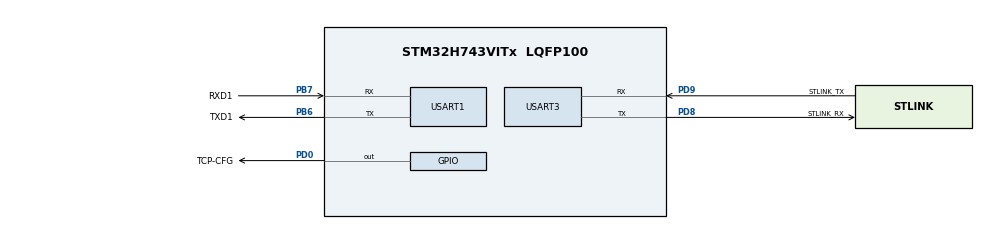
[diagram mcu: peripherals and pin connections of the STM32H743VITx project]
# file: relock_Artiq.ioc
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CORTEX_M7.CPU_DCache=Disabled
CORTEX_M7.CPU_ICache=Disabled
CORTEX_M7.MPU_Control=__NULL
CORTEX_M7.default_mode_Activation=0
Mcu.Family=STM32H7
Mcu.Name=STM32H743VITx
Mcu.Package=LQFP100
NVIC.PriorityGroup=NVIC_PRIORITYGROUP_4
PA13\ (JTMS/SWDIO).Mode=JTAG_4_pins
PA13\ (JTMS/SWDIO).Signal=DEBUG_JTMS-SWDIO
PA14\ (JTCK/SWCLK).Mode=JTAG_4_pins
PA14\ (JTCK/SWCLK).Signal=DEBUG_JTCK-SWCLK
PA15\ (JTDI).Mode=JTAG_4_pins
PA15\ (JTDI).Signal=DEBUG_JTDI
PB3\ (JTDO/TRACESWO).Mode=JTAG_4_pins
PB3\ (JTDO/TRACESWO).Signal=DEBUG_JTDO-SWO
PB6.GPIO_Label=TXD1
PB6.Mode=Asynchronous
PB6.Signal=USART1_TX
PB7.GPIO_Label=RXD1
PB7.Mode=Asynchronous
PB7.Signal=USART1_RX
PD0.GPIO_Label=TCP-CFG
PD0.PinState=GPIO_PIN_SET
PD0.Signal=GPIO_Output
PD8.GPIO_Label=STLINK_RX
PD8.Mode=Asynchronous
PD8.Signal=USART3_TX
PD9.GPIO_Label=STLINK_TX
PD9.Mode=Asynchronous
PD9.Signal=USART3_RX
PH0-OSC_IN\ (PH0).Mode=HSE-External-Oscillator
PH0-OSC_IN\ (PH0).Signal=RCC_OSC_IN
PH1-OSC_OUT\ (PH1).Mode=HSE-External-Oscillator
PH1-OSC_OUT\ (PH1).Signal=RCC_OSC_OUT
ProjectManager.HeapSize=0x200
ProjectManager.StackSize=0x400
ProjectManager.TargetToolchain=STM32CubeIDE
RCC.ADCFreq_Value=75000000
RCC.APB1Freq_Value=75000000
RCC.APB2Freq_Value=75000000
RCC.APB3Freq_Value=75000000
RCC.APB4Freq_Value=75000000
RCC.CortexFreq_Value=75000000
RCC.DIVM1=1
RCC.DIVM2=1
RCC.DIVN1=18
RCC.DIVN2=18
RCC.DIVQ1=3
RCC.HCLKFreq_Value=75000000
RCC.HSE_VALUE=8000000
RCC.PLLSourceVirtual=RCC_PLLSOURCE_HSE
RCC.SYSCLKFreq_VALUE=75000000
RCC.SYSCLKSource=RCC_SYSCLKSOURCE_PLLCLK
RCC.USBFreq_Value=50000000
USART1.VirtualMode-Asynchronous=VM_ASYNC
USART3.VirtualMode-Asynchronous=VM_ASYNC
VP_MEMORYMAP_VS_MEMORYMAP.Mode=CurAppReg
board=NUCLEO-H743ZI2

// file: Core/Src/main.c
/* USER CODE BEGIN Header */
/**
  ******************************************************************************
  * @file           : main.c
  * @brief          : Main program body
  ******************************************************************************
  * @attention
  *
  * Copyright (c) 2024 STMicroelectronics.
  * All rights reserved.
  *
  * This software is licensed under terms that can be found in the LICENSE file
  * in the root directory of this software component.
  * If no LICENSE file comes with this software, it is provided AS-IS.
  *
  ******************************************************************************
  */
/* USER CODE END Header */
#include "main.h"

/* USER CODE BEGIN Includes */
#include "interface.h"
/* USER CODE END Includes */

/* USER CODE BEGIN PD */
#define FLASH_PARAM_START_ADDR  ((uint32_t)0x081E0000)  // bank 2, sektor 7
#define FLASH_WORD_SIZE        (32)  // Flash word = 256-bit = 32 bytes
#define BUFFER_SIZE 100
#define MAX(a,b) (((a)>(b))?(a):(b))
/* USER CODE END PD */

UART_HandleTypeDef huart1;
UART_HandleTypeDef huart3;

/* USER CODE BEGIN PV */
uint8_t rxChar;
  uint8_t rxBuffer[BUFFER_SIZE];
  uint8_t txBuffer[BUFFER_SIZE];
  uint8_t tmpBuffer[BUFFER_SIZE];
  uint16_t index = 0;
  uint8_t helloMsg[] = "\nADDA>";
  HAL_StatusTypeDef status;

void Flash_Write_Params(uint32_t address, parameters *data) {
  HAL_FLASH_Unlock();  // Odblokowanie pamięci flash

  FLASH_EraseInitTypeDef eraseInitStruct;
  uint32_t sectorError;

  // Kasowanie sektora przed zapisem
  eraseInitStruct.TypeErase    = FLASH_TYPEERASE_SECTORS;
  eraseInitStruct.Banks        = FLASH_BANK_2;  // **Bank 2**
  eraseInitStruct.Sector       = FLASH_SECTOR_7;  // **Sektor 7**
  eraseInitStruct.NbSectors    = 1;
  eraseInitStruct.VoltageRange = FLASH_VOLTAGE_RANGE_3;

  if (HAL_FLASHEx_Erase(&eraseInitStruct, &sectorError) != HAL_OK) {
      HAL_FLASH_Lock();
      return;  // Błąd kasowania
  }

  uint64_t *data_ptr = (uint64_t*)data;
  uint64_t flash_word[4];
  for (uint32_t i = 0; i < sizeof(parameters) / 8; i += 4) {
      flash_word[0] = (i < sizeof(parameters) / 8) ? data_ptr[i] : 0xFFFFFFFFFFFFFFFF;
      flash_word[1] = (i + 1 < sizeof(parameters) / 8) ? data_ptr[i + 1] : 0xFFFFFFFFFFFFFFFF;
      flash_word[2] = (i + 2 < sizeof(parameters) / 8) ? data_ptr[i + 2] : 0xFFFFFFFFFFFFFFFF;
      flash_word[3] = (i + 3 < sizeof(parameters) / 8) ? data_ptr[i + 3] : 0xFFFFFFFFFFFFFFFF;

      if (HAL_FLASH_Program(FLASH_TYPEPROGRAM_FLASHWORD, address + i * 8, (uint64_t)flash_word) != HAL_OK) {
          HAL_FLASH_Lock();
          return;  // Błąd zapisu
      }
  }

  HAL_FLASH_Lock();  // Zablokowanie pamięci flash
}

void Flash_Read_Params(uint32_t address, parameters *data) {
  memcpy(data, (void*)address, sizeof(parameters));  // Odczytaj całą strukturę
}

uint32_t Flash_Read_Version(uint32_t address) {
  return *(volatile double*)address;  // Odczytaj pierwsze 4 bajty
}

/* USER CODE END PV */

void SystemClock_Config(void);
static void MX_GPIO_Init(void);
static void MX_USART3_UART_Init(void);
static void MX_USART1_UART_Init(void);
/* USER CODE BEGIN PFP */
void SendSpiMesToDac(uint32_t);
void SetDAC(uint8_t channel, uint16_t value);
void SendToDAC(int r);
int ExtractMessageOld(char* msg, char* out);
void ExtractMessage(char* rxBuffer, char* txBuffer);
void arrayToString(double DAC[4][4], char *result);
void update_array();
/* USER CODE END PFP */

/* USER CODE BEGIN 0 */
extern parameters par;
/* USER CODE END 0 */

int main(void)
{

  /* MCU Configuration--------------------------------------------------------*/

  /* Reset of all peripherals, Initializes the Flash interface and the Systick. */
  HAL_Init();

  /* Configure the system clock */
  SystemClock_Config();

  /* Initialize all configured peripherals */
  MX_GPIO_Init();
  MX_USART3_UART_Init();
  MX_USART1_UART_Init();
  /* USER CODE BEGIN 2 */

  initInterface();

  // read par from flash
  if (par.version != Flash_Read_Version(FLASH_PARAM_START_ADDR)){
    Flash_Write_Params(FLASH_PARAM_START_ADDR, &par);
  }
  else{
    Flash_Read_Params(FLASH_PARAM_START_ADDR, &par);
  }

  /* USER CODE END 2 */

  /* Infinite loop */
  /* USER CODE BEGIN WHILE */
  while (1)
  {
	  status = HAL_UART_Receive(&huart1, &rxChar, 1, HAL_MAX_DELAY);
	  	  	  	  if (status == HAL_OK)
	  	  	  	  {
	  	  	  		  if ((rxChar == '\r' || rxChar == '\n') && index>0){
	  	  	  			  rxBuffer[index++]='\n';
	  	  	  			  rxBuffer[index++]='\0';
	  	  	  			  ExtractMessage((char*) rxBuffer, (char*) txBuffer);
	  //	  	  			  strcpy(tmpBuffer, helloMsg);
	  	  	  			  strcat(tmpBuffer, txBuffer);
	  	  	  			  strcpy(txBuffer, tmpBuffer);

	  	  	  			  HAL_UART_Transmit(&huart1, txBuffer, strlen(txBuffer), HAL_MAX_DELAY);
	  	  	  			  HAL_UART_Transmit(&huart1, helloMsg, strlen(helloMsg), HAL_MAX_DELAY);
	  	  	  			  index=0;
	  	  	  		  }
	  	  	  		  else{
	  	  	  			  rxBuffer[index++] = rxChar;
	  	  	  			  if (index >= BUFFER_SIZE) index = 0;
	  	  	  		  }
	  	  	  	  }
    /* USER CODE END WHILE */

  }
}

void SystemClock_Config(void)
{
  RCC_OscInitTypeDef RCC_OscInitStruct = {0};
  RCC_ClkInitTypeDef RCC_ClkInitStruct = {0};

  /** Supply configuration update enable
  */
  HAL_PWREx_ConfigSupply(PWR_LDO_SUPPLY);

  /** Configure the main internal regulator output voltage
  */
  __HAL_PWR_VOLTAGESCALING_CONFIG(PWR_REGULATOR_VOLTAGE_SCALE3);

  while(!__HAL_PWR_GET_FLAG(PWR_FLAG_VOSRDY)) {}

  /** Initializes the RCC Oscillators according to the specified parameters
  * in the RCC_OscInitTypeDef structure.
  */
  RCC_OscInitStruct.OscillatorType = RCC_OSCILLATORTYPE_HSE;
  RCC_OscInitStruct.HSEState = RCC_HSE_ON;
  RCC_OscInitStruct.PLL.PLLState = RCC_PLL_ON;
  RCC_OscInitStruct.PLL.PLLSource = RCC_PLLSOURCE_HSE;
  RCC_OscInitStruct.PLL.PLLM = 1;
  RCC_OscInitStruct.PLL.PLLN = 18;
  RCC_OscInitStruct.PLL.PLLP = 2;
  RCC_OscInitStruct.PLL.PLLQ = 3;
  RCC_OscInitStruct.PLL.PLLR = 2;
  RCC_OscInitStruct.PLL.PLLRGE = RCC_PLL1VCIRANGE_3;
  RCC_OscInitStruct.PLL.PLLVCOSEL = RCC_PLL1VCOMEDIUM;
  RCC_OscInitStruct.PLL.PLLFRACN = 0;
  if (HAL_RCC_OscConfig(&RCC_OscInitStruct) != HAL_OK)
  {
    Error_Handler();
  }

  /** Initializes the CPU, AHB and APB buses clocks
  */
  RCC_ClkInitStruct.ClockType = RCC_CLOCKTYPE_HCLK|RCC_CLOCKTYPE_SYSCLK
                              |RCC_CLOCKTYPE_PCLK1|RCC_CLOCKTYPE_PCLK2
                              |RCC_CLOCKTYPE_D3PCLK1|RCC_CLOCKTYPE_D1PCLK1;
  RCC_ClkInitStruct.SYSCLKSource = RCC_SYSCLKSOURCE_PLLCLK;
  RCC_ClkInitStruct.SYSCLKDivider = RCC_SYSCLK_DIV1;
  RCC_ClkInitStruct.AHBCLKDivider = RCC_HCLK_DIV1;
  RCC_ClkInitStruct.APB3CLKDivider = RCC_APB3_DIV1;
  RCC_ClkInitStruct.APB1CLKDivider = RCC_APB1_DIV1;
  RCC_ClkInitStruct.APB2CLKDivider = RCC_APB2_DIV1;
  RCC_ClkInitStruct.APB4CLKDivider = RCC_APB4_DIV1;

  if (HAL_RCC_ClockConfig(&RCC_ClkInitStruct, FLASH_LATENCY_1) != HAL_OK)
  {
    Error_Handler();
  }
}

static void MX_USART1_UART_Init(void)
{

  huart1.Instance = USART1;
  huart1.Init.BaudRate = 115200;
  huart1.Init.WordLength = UART_WORDLENGTH_8B;
  huart1.Init.StopBits = UART_STOPBITS_1;
  huart1.Init.Parity = UART_PARITY_NONE;
  huart1.Init.Mode = UART_MODE_TX_RX;
  huart1.Init.HwFlowCtl = UART_HWCONTROL_NONE;
  huart1.Init.OverSampling = UART_OVERSAMPLING_16;
  huart1.Init.OneBitSampling = UART_ONE_BIT_SAMPLE_DISABLE;
  huart1.Init.ClockPrescaler = UART_PRESCALER_DIV1;
  huart1.AdvancedInit.AdvFeatureInit = UART_ADVFEATURE_NO_INIT;
  if (HAL_UART_Init(&huart1) != HAL_OK)
  {
    Error_Handler();
  }
  if (HAL_UARTEx_SetTxFifoThreshold(&huart1, UART_TXFIFO_THRESHOLD_1_8) != HAL_OK)
  {
    Error_Handler();
  }
  if (HAL_UARTEx_SetRxFifoThreshold(&huart1, UART_RXFIFO_THRESHOLD_1_8) != HAL_OK)
  {
    Error_Handler();
  }
  if (HAL_UARTEx_DisableFifoMode(&huart1) != HAL_OK)
  {
    Error_Handler();
  }

}

static void MX_USART3_UART_Init(void)
{

  huart3.Instance = USART3;
  huart3.Init.BaudRate = 115200;
  huart3.Init.WordLength = UART_WORDLENGTH_8B;
  huart3.Init.StopBits = UART_STOPBITS_1;
  huart3.Init.Parity = UART_PARITY_NONE;
  huart3.Init.Mode = UART_MODE_TX_RX;
  huart3.Init.HwFlowCtl = UART_HWCONTROL_NONE;
  huart3.Init.OverSampling = UART_OVERSAMPLING_16;
  huart3.Init.OneBitSampling = UART_ONE_BIT_SAMPLE_DISABLE;
  huart3.Init.ClockPrescaler = UART_PRESCALER_DIV1;
  huart3.AdvancedInit.AdvFeatureInit = UART_ADVFEATURE_NO_INIT;
  if (HAL_UART_Init(&huart3) != HAL_OK)
  {
    Error_Handler();
  }
  if (HAL_UARTEx_SetTxFifoThreshold(&huart3, UART_TXFIFO_THRESHOLD_1_8) != HAL_OK)
  {
    Error_Handler();
  }
  if (HAL_UARTEx_SetRxFifoThreshold(&huart3, UART_RXFIFO_THRESHOLD_1_8) != HAL_OK)
  {
    Error_Handler();
  }
  if (HAL_UARTEx_DisableFifoMode(&huart3) != HAL_OK)
  {
    Error_Handler();
  }

}

static void MX_GPIO_Init(void)
{
  GPIO_InitTypeDef GPIO_InitStruct = {0};

  /* GPIO Ports Clock Enable */
  __HAL_RCC_GPIOH_CLK_ENABLE();
  __HAL_RCC_GPIOD_CLK_ENABLE();
  __HAL_RCC_GPIOA_CLK_ENABLE();
  __HAL_RCC_GPIOB_CLK_ENABLE();

  /*Configure GPIO pin Output Level */
  HAL_GPIO_WritePin(TCP_CFG_GPIO_Port, TCP_CFG_Pin, GPIO_PIN_SET);

  /*Configure GPIO pin : TCP_CFG_Pin */
  GPIO_InitStruct.Pin = TCP_CFG_Pin;
  GPIO_InitStruct.Mode = GPIO_MODE_OUTPUT_PP;
  GPIO_InitStruct.Pull = GPIO_NOPULL;
  GPIO_InitStruct.Speed = GPIO_SPEED_FREQ_LOW;
  HAL_GPIO_Init(TCP_CFG_GPIO_Port, &GPIO_InitStruct);

}

/* USER CODE BEGIN 4 */
void HAL_GPIO_EXTI_Callback(uint16_t GPIO_Pin)
{

}

void ExtractMessage(char* rxBuffer, char* txBuffer)
// I am not sure we need it, may be from another project
{
    cmd_string_interpret(rxBuffer, txBuffer);
    txBuffer[BUFFER_SIZE - 1] = '\0';
}

/* USER CODE END 4 */

void Error_Handler(void)
{
  __disable_irq();
  while (1)
  {
  }
}
